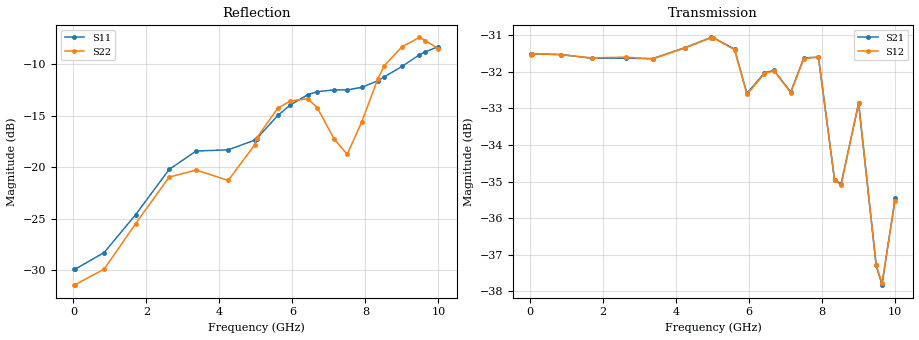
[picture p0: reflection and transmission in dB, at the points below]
! Integrated Device Technology
! Corporate Headquarters
! 6024 Silver Creek Valley Road
! San Jose, CA 95138  USA
! Phone:  1-408-284-8200
! Toll Free:  1-800-223-1366
! Webpage:  http://www.idt.com/
! Timing and RF Division
! 515 Groton Road, Suite 102
! Westford, MA 01886-6024
! Device:  F1958
! Description: 7-bit 0.25 dB Digital Step Attenuator
! Frequency:  0.001 -  6.000 GHz
! Package:  4x4 mm Thin QFN Plastic Package: 24 pin
! Ports:  2 RF, 12 DC
!  Pin  1  = D0
!  Pin  2  = VDD
!  Pin  3  = VMODE
!  Pin  4  = GND
!  Pin  5  = RF1  =  Port 1
!  Pin  6  = GND
!  Pin  7  = GND
!  Pin  8  = GND
!  Pin  9  = GND
!  Pin 10  = GND
!  Pin 11  = GND
!  Pin 12  = GND
!  Pin 13  = GND
!  Pin 14  = RF2  =  Port 2
!  Pin 15  = GND
!  Pin 16  = LE
!  Pin 17  = CLK
!  Pin 18  = DATA
!  Pin 19  = D6
!  Pin 20  = D5
!  Pin 21  = D4
!  Pin 22  = D3
!  Pin 23  = D2
!  Pin 24  = D1
! State:  123
! Atten State:  30.75 dB
! Voltage:  +3.30 Volts
! Current:  0.259 mA
! Data:  The device was measured on a F1958 evaluation board which has
!  individual transmission lines to the RF pins.  Data was collected
!  using a calibrated network analyzer.  The evaluation board was
!  de-embedded using Automatic Fixture Removal (AFR).
!  The reference plane is the edge of the package pin.
! Misc:
!  Action Tracker AT0419
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# GHz S dB R 50
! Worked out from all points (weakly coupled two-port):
!   500 points, 20 MHz to 10 GHz, reference 50 ohm
!   highest |S21| = -31.06 dB at 4.96 GHz (marker M1); lowest = -37.8 dB at 9.64 GHz (marker M2)
!   lowest |S11| = -29.9 dB at 40 MHz (marker M3), VSWR 1.07, Z = 46.9 - j0.0464 ohm
!   |S11| at or under -10 dB: start of sweep to 9.055 GHz
!   |S22| runs from -31.6 to -7.4 dB; largest |S21 - S12| = 0.00028
!   S11 on the Smith chart (normalised r, x): 20 MHz: 0.94, -0.00; 6.42 GHz: 0.66, +0.17; 10 GHz: 0.67, +0.60
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0.02  -29.87 -178.9  -31.52 -0.1  -31.53 -0.1  -31.44 -179.0
0.04  -29.90 -179.1  -31.51 -0.2  -31.51 -0.2  -31.40 -178.4
0.84  -28.28 171.7  -31.53 -8.9  -31.53 -8.9  -29.89 172.7
1.7  -24.62 171.7  -31.63 -17.6  -31.62 -17.6  -25.49 171.4
2.62  -20.22 177.3  -31.63 -27.1  -31.60 -27.1  -20.96 -179.8
3.36  -18.43 -175.7  -31.64 -35.3  -31.65 -35.3  -20.27 -170.1
4.24  -18.31 -179.2  -31.34 -44.5  -31.35 -44.6  -21.28 168.2
4.96  -17.38 162.1  -31.06 -53.1  -31.07 -53.2  -17.85 139.2
5.02  -17.22 160.8  -31.07 -54.4  -31.07 -54.4  -17.15 138.1
5.6  -14.97 150.8  -31.38 -63.0  -31.40 -63.0  -14.27 139.9
5.94  -13.96 148.3  -32.59 -66.2  -32.62 -66.3  -13.57 148.1
6.42  -12.96 147.4  -32.03 -71.6  -32.05 -71.5  -13.35 156.4
6.68  -12.67 146.4  -31.96 -73.9  -31.97 -73.9  -14.23 156.8
7.14  -12.49 142.5  -32.55 -78.7  -32.57 -78.6  -17.25 150.6
7.5  -12.49 137.9  -31.62 -82.3  -31.64 -82.2  -18.75 118.8
7.9  -12.25 128.6  -31.60 -98.7  -31.60 -98.7  -15.58 89.0
8.34  -11.61 118.6  -34.95 -103.7  -34.96 -103.9  -11.42 83.8
8.52  -11.22 115.2  -35.06 -94.5  -35.10 -94.4  -10.13 87.2
9  -10.22 108.2  -32.86 -103.0  -32.86 -103.2  -8.32 97.3
9.48  -9.09 101.5  -37.28 -108.8  -37.29 -108.4  -7.40 107.4
9.64  -8.80 100.9  -37.83 -97.6  -37.77 -97.7  -7.72 110.3
10  -8.29 99.4  -35.45 -81.6  -35.52 -82.0  -8.51 113.6
